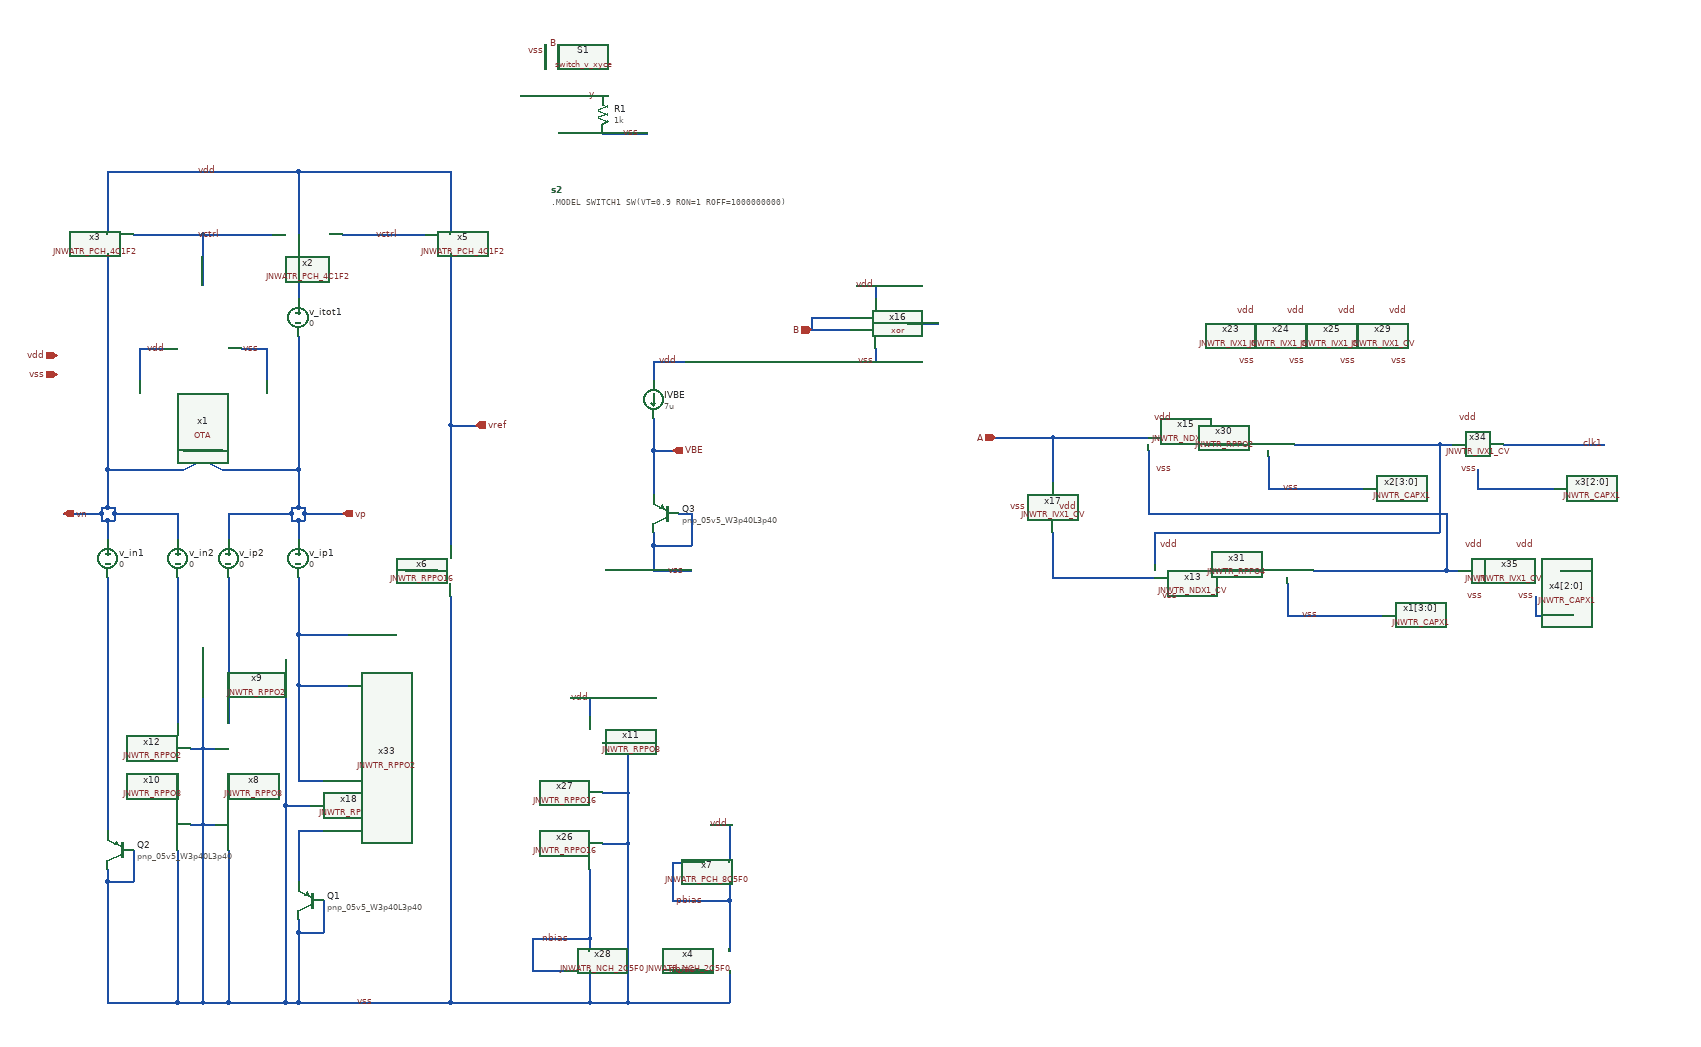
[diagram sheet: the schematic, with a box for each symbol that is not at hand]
v {xschem version=3.4.6 file_version=1.2}
G {}
K {}
V {}
S {}
E {}
N 870 -120 960 -120 {
lab=nbias}
N 960 -120 960 -100 {
lab=nbias}
N 1180 -210 1180 -180 {
lab=pbias}
N 1090 -180 1180 -180 {
lab=pbias}
N 1090 -240 1090 -180 {
lab=pbias}
N 1090 -240 1140 -240 {
lab=pbias}
N 1180 -300 1180 -240 {
lab=vdd}
N 960 -70 960 -20 {
lab=vss}
N 930 -500 960 -500 {
lab=vdd}
N 1020 -270 1020 -20 {
lab=vss}
N 980 -270 1020 -270 {
lab=vss}
N 1020 -350 1020 -270 {
lab=vss}
N 980 -350 1020 -350 {
lab=vss}
N 1020 -430 1020 -350 {
lab=vss}
N 980 -430 1020 -430 {
lab=vss}
N 960 -500 960 -470 {
lab=vdd}
N 1090 -70 1140 -70 {
lab=nbias}
N 1020 -20 1180 -20 {
lab=vss}
N 1150 -300 1180 -300 {
lab=vdd}
N 870 -120 870 -70 {
lab=nbias}
N 870 -70 920 -70 {
lab=nbias}
N 1180 -70 1180 -20 {
lab=vss}
N 1180 -180 1180 -100 {
lab=pbias}
N 960 -230 960 -120 {
lab=nbias}
N 490 -790 490 -780 {
lab=vp}
N 500 -800 510 -800 {
lab=vp}
N 210 -790 210 -780 {
lab=vn}
N 200 -800 210 -800 {
lab=vn}
N 510 -790 510 -780 {
lab=vp}
N 210 -800 210 -790 {
lab=vn}
N 490 -800 490 -790 {
lab=vp}
N 390 -790 490 -790 {
lab=vp}
N 200 -780 210 -780 {
lab=vn}
N 210 -790 310 -790 {
lab=vn}
N 190 -790 190 -780 {
lab=vn}
N 240 -260 240 -210 {
lab=vss}
N 200 -210 240 -210 {
lab=vss}
N 200 -230 200 -210 {
lab=vss}
N 540 -180 540 -130 {
lab=vss}
N 500 -130 540 -130 {
lab=vss}
N 500 -150 500 -130 {
lab=vss}
N 500 -780 510 -780 {
lab=vp}
N 380 -860 500 -860 {
lab=vp}
N 200 -860 200 -800 {
lab=vn}
N 190 -800 200 -800 {
lab=vn}
N 500 -860 500 -800 {
lab=vp}
N 490 -800 500 -800 {
lab=vp}
N 200 -1200 200 -860 {
lab=vn}
N 200 -860 320 -860 {
lab=vn}
N 350 -1230 350 -1150 {
lab=vctrl}
N 350 -1230 460 -1230 {
lab=vctrl}
N 240 -1230 350 -1230 {
lab=vctrl}
N 200 -1330 200 -1230 {
lab=vdd}
N 200 -1330 500 -1330 {
lab=vdd}
N 740 -1330 740 -1230 {
lab=vdd}
N 500 -1330 740 -1330 {
lab=vdd}
N 500 -1330 500 -1230 {
lab=vdd}
N 740 -930 740 -740 {
lab=vref}
N 510 -790 570 -790 {
lab=vp}
N 510 -800 510 -790 {
lab=vp}
N 130 -790 190 -790 {
lab=vn}
N 190 -800 190 -790 {
lab=vn}
N 740 -930 780 -930 {
lab=vref}
N 740 -1200 740 -930 {
lab=vref}
N 570 -1230 700 -1230 {
lab=vctrl}
N 500 -130 500 -20 {
lab=vss}
N 200 -210 200 -20 {
lab=vss}
N 500 -20 740 -20 {
lab=vss}
N 670 -700 720 -700 {
lab=vss}
N 740 -660 740 -20 {
lab=vss}
N 960 -20 1020 -20 {
lab=vss}
N 740 -20 960 -20 {
lab=vss}
N 480 -20 500 -20 {
lab=vss}
N 500 -1200 500 -1130 {
lab=#net1}
N 500 -780 500 -750 {
lab=vp}
N 490 -780 500 -780 {
lab=vp}
N 390 -790 390 -750 {
lab=vp}
N 200 -780 200 -750 {
lab=vn}
N 190 -780 200 -780 {
lab=vn}
N 200 -690 200 -290 {
lab=#net2}
N 310 -790 310 -750 {
lab=vn}
N 1060 -890 1060 -820 {
lab=VBE}
N 1060 -740 1060 -700 {
lab=vss}
N 1060 -700 1120 -700 {
lab=vss}
N 1060 -1030 1060 -1000 {
lab=vdd}
N 1060 -1030 1110 -1030 {
lab=vdd}
N 1060 -890 1090 -890 {
lab=VBE}
N 1060 -940 1060 -890 {
lab=VBE}
N 1100 -790 1120 -790 {
lab=vss}
N 1120 -790 1120 -740 {
lab=vss}
N 1060 -740 1120 -740 {
lab=vss}
N 1060 -760 1060 -740 {
lab=vss}
N 1310 -1100 1370 -1100 {
lab=B}
N 1310 -1080 1370 -1080 {
lab=B}
N 1410 -1150 1410 -1130 {
lab=vdd}
N 1380 -1150 1410 -1150 {
lab=vdd}
N 1410 -1050 1410 -1030 {
lab=vss}
N 1380 -1030 1410 -1030 {
lab=vss}
N 1460 -1090 1510 -1090 {
lab=#net3}
N 500 -520 500 -370 {
lab=#net4}
N 350 -300 370 -300 {
lab=vss}
N 330 -300 350 -300 {
lab=vss}
N 350 -420 370 -420 {
lab=vss}
N 330 -420 350 -420 {
lab=vss}
N 350 -420 350 -300 {
lab=vss}
N 350 -580 350 -420 {
lab=vss}
N 500 -520 580 -520 {
lab=#net4}
N 500 -600 580 -600 {
lab=#net4}
N 310 -690 310 -460 {
lab=#net5}
N 390 -690 390 -460 {
lab=#net6}
N 500 -690 500 -600 {
lab=#net4}
N 500 -290 500 -210 {
lab=#net7}
N 480 -330 480 -20 {
lab=vss}
N 390 -20 480 -20 {
lab=vss}
N 350 -300 350 -20 {
lab=vss}
N 310 -260 310 -20 {
lab=vss}
N 200 -20 310 -20 {
lab=vss}
N 390 -260 390 -20 {
lab=vss}
N 350 -20 390 -20 {
lab=vss}
N 310 -20 350 -20 {
lab=vss}
N 500 -1070 500 -860 {
lab=vp}
N 320 -860 380 -890 {
lab=vn}
N 320 -890 380 -860 {
lab=vp}
N 250 -1050 250 -1000 {
lab=vdd}
N 250 -1050 290 -1050 {
lab=vdd}
N 450 -1050 450 -1000 {
lab=vss}
N 410 -1050 450 -1050 {
lab=vss}
N 940 -1450 980 -1450 {
lab=y}
N 890 -1530 890 -1490 {
lab=vss}
N 910 -1530 910 -1490 {
lab=B}
N 850 -1450 880 -1450 {
lab=#net8}
N 980 -1390 1050 -1390 {
lab=vss}
N 1690 -760 1690 -690 {
lab=#net9}
N 1690 -690 1850 -690 {
lab=#net9}
N 1690 -910 1840 -910 {
lab=A}
N 1690 -910 1690 -840 {
lab=A}
N 1600 -910 1690 -910 {
lab=A}
N 1940 -700 2020 -700 {
lab=#net10}
N 2310 -790 2310 -700 {
lab=#net11}
N 1840 -790 2310 -790 {
lab=#net11}
N 1840 -890 1840 -790 {
lab=#net11}
N 1930 -900 1990 -900 {
lab=#net12}
N 2300 -900 2300 -760 {
lab=#net13}
N 1850 -760 2300 -760 {
lab=#net13}
N 1850 -760 1850 -710 {
lab=#net13}
N 1310 -1100 1310 -1080 {
lab=B}
N 2300 -900 2320 -900 {
lab=#net13}
N 2060 -680 2060 -630 {
lab=vss}
N 2100 -700 2310 -700 {
lab=#net11}
N 2060 -630 2210 -630 {
lab=vss}
N 2030 -880 2030 -830 {
lab=vss}
N 2070 -900 2300 -900 {
lab=#net13}
N 2030 -830 2180 -830 {
lab=vss}
N 2310 -700 2330 -700 {
lab=#net11}
N 2400 -900 2560 -900 {
lab=clk1}
N 2490 -700 2530 -700 {
lab=clk2}
N 2450 -660 2450 -630 {
lab=vss}
N 2450 -630 2510 -630 {
lab=vss}
N 2360 -860 2360 -830 {
lab=vss}
N 2360 -830 2480 -830 {
lab=vss}
N 480 -330 520 -330 {lab=vss}
N 480 -560 480 -330 {
lab=vss}
N 500 -370 540 -370 {lab=#net4}
N 500 -290 540 -290 {lab=#net7}
N 500 -600 500 -520 {lab=#net4}
N 390 -380 390 -340 {lab=#net14}
N 310 -380 310 -340 {lab=#net15}
C {devices/ipin.sym} 120 -1010 0 0 {name=p4 lab=vss}
C {devices/ipin.sym} 120 -1040 0 0 {name=p5 lab=vdd}
C {devices/lab_wire.sym} 1140 -180 0 0 {name=p32 sig_type=std_logic lab=pbias}
C {devices/lab_wire.sym} 960 -500 0 0 {name=p34 sig_type=std_logic lab=vdd}
C {JNW_ATR_SKY130A/JNWATR_PCH_8C5F0.sym} 1140 -240 0 0 {name=x7 }
C {JNW_ATR_SKY130A/JNWATR_NCH_2C5F0.sym} 920 -70 0 0 {name=x28 }
C {devices/lab_wire.sym} 930 -120 0 0 {name=p12 sig_type=std_logic lab=nbias}
C {devices/lab_wire.sym} 1180 -300 0 0 {name=p13 sig_type=std_logic lab=vdd}
C {JNW_ATR_SKY130A/JNWATR_NCH_2C5F0.sym} 1140 -70 0 0 {name=x4 }
C {devices/lab_wire.sym} 1130 -70 0 0 {name=p14 sig_type=std_logic lab=nbias}
C {JNW_TR_SKY130A/JNWTR_RPPO16.sym} 960 -230 3 0 {name=x26 }
C {JNW_TR_SKY130A/JNWTR_RPPO16.sym} 960 -310 3 0 {name=x27 }
C {JNW_TR_SKY130A/JNWTR_RPPO8.sym} 960 -390 3 0 {name=x11 }
C {sky130_fd_pr/pnp_05v5.sym} 520 -180 0 1 {name=Q1
model=pnp_05v5_W3p40L3p40
m=8
spiceprefix=X
}
C {sky130_fd_pr/pnp_05v5.sym} 220 -260 0 1 {name=Q2
model=pnp_05v5_W3p40L3p40
m=1
spiceprefix=X
}
C {devices/lab_wire.sym} 340 -1330 0 1 {name=p29 sig_type=std_logic lab=vdd

}
C {devices/opin.sym} 130 -790 2 0 {name=p44 lab=vn}
C {JNW_ATR_SKY130A/JNWATR_PCH_4C1F2.sym} 460 -1230 0 0 {name=x2 }
C {JNW_ATR_SKY130A/JNWATR_PCH_4C1F2.sym} 240 -1230 0 1 {name=x3 }
C {JNW_ATR_SKY130A/JNWATR_PCH_4C1F2.sym} 700 -1230 0 0 {name=x5 }
C {devices/lab_wire.sym} 340 -1230 0 1 {name=p8 sig_type=std_logic lab=vctrl

}
C {devices/lab_wire.sym} 620 -1230 0 1 {name=p9 sig_type=std_logic lab=vctrl

}
C {devices/lab_wire.sym} 620 -20 0 0 {name=p3 sig_type=std_logic lab=vss
}
C {devices/opin.sym} 570 -790 0 0 {name=p7 lab=vp}
C {devices/opin.sym} 780 -930 0 0 {name=p10 lab=vref}
C {devices/lab_wire.sym} 700 -700 0 0 {name=p11 sig_type=std_logic lab=vss
}
C {JNW_TR_SKY130A/JNWTR_RPPO16.sym} 740 -740 1 0 {name=x6 }
C {devices/vsource.sym} 500 -1100 0 0 {name=v_itot1 value=0 savecurrent=true}
C {devices/vsource.sym} 500 -720 0 0 {name=v_ip1 value=0 savecurrent=true}
C {devices/vsource.sym} 390 -720 0 0 {name=v_ip2 value=0 savecurrent=true}
C {devices/vsource.sym} 200 -720 0 0 {name=v_in1 value=0 savecurrent=true}
C {devices/vsource.sym} 310 -720 0 0 {name=v_in2 value=0 savecurrent=true}
C {devices/isource.sym} 1060 -970 0 0 {name=IVBE value=7u}
C {devices/lab_wire.sym} 1100 -1030 0 0 {name=p15 sig_type=std_logic lab=vdd}
C {devices/lab_wire.sym} 1110 -700 0 0 {name=p16 sig_type=std_logic lab=vss
}
C {devices/opin.sym} 1090 -890 0 0 {name=p17 lab=VBE}
C {sky130_fd_pr/pnp_05v5.sym} 1080 -790 0 1 {name=Q3
model=pnp_05v5_W3p40L3p40
m=1
spiceprefix=X
}
C {devices/ipin.sym} 1310 -1080 0 0 {name=p18 lab=B}
C {JNW_AVV_SKY130A/xor.sym} 1410 -1090 0 0 {name=x16}
C {devices/lab_wire.sym} 1410 -1150 0 0 {name=p20 sig_type=std_logic lab=vdd}
C {devices/lab_wire.sym} 1410 -1030 0 0 {name=p21 sig_type=std_logic lab=vss
}
C {JNW_TR_SKY130A/JNWTR_RPPO2.sym} 500 -370 1 0 {name=x18 }
C {JNW_AVV_SKY130A/OTA.sym} 350 -1000 3 0 {name=x1}
C {devices/lab_wire.sym} 260 -1050 0 1 {name=p1 sig_type=std_logic lab=vdd

}
C {devices/lab_wire.sym} 440 -1050 0 0 {name=p2 sig_type=std_logic lab=vss
}
C {devices/lab_wire.sym} 890 -1520 0 0 {name=p6 sig_type=std_logic lab=vss
}
C {devices/lab_wire.sym} 910 -1530 0 0 {name=p24 sig_type=std_logic lab=B
}
C {devices/lab_wire.sym} 970 -1450 0 0 {name=p25 sig_type=std_logic lab=y
}
C {devices/switch_v_xyce.sym} 910 -1450 1 0 {.MODEL SWITCH1 SW(VT=0.5 VH=0.01 RON=0.01 ROFF=10000000)

name=S1 model=SWITCH1 state=OFF

}
C {devices/netlist.sym} 900 -1300 0 0 {name=s2 value=".MODEL SWITCH1 SW(VT=0.9 RON=1 ROFF=1000000000)"
}
C {devices/res.sym} 980 -1420 0 0 {name=R1
value=1k
footprint=1206
device=resistor
m=1}
C {devices/lab_wire.sym} 1040 -1390 0 0 {name=p22 sig_type=std_logic lab=vss
}
C {JNW_TR_SKY130A/JNWTR_NDX1_CV.sym} 1850 -690 0 0 {name=x13 }
C {devices/lab_wire.sym} 1890 -740 0 0 {name=p26 sig_type=std_logic lab=vdd}
C {devices/lab_wire.sym} 1890 -660 0 0 {name=p27 sig_type=std_logic lab=vss
}
C {JNW_TR_SKY130A/JNWTR_NDX1_CV.sym} 1840 -890 0 0 {name=x15 }
C {devices/lab_wire.sym} 1880 -940 0 0 {name=p28 sig_type=std_logic lab=vdd}
C {devices/lab_wire.sym} 1880 -860 0 0 {name=p30 sig_type=std_logic lab=vss
}
C {JNW_TR_SKY130A/JNWTR_IVX1_CV.sym} 1690 -840 1 0 {name=x17 }
C {devices/lab_wire.sym} 1650 -800 0 0 {name=p31 sig_type=std_logic lab=vss
}
C {devices/lab_wire.sym} 1730 -800 0 0 {name=p33 sig_type=std_logic lab=vdd}
C {devices/ipin.sym} 1600 -910 0 0 {name=p35 lab=A}
C {JNW_TR_SKY130A/JNWTR_IVX1_CV.sym} 1970 -1070 0 0 {name=x23 }
C {devices/lab_wire.sym} 2010 -1030 3 0 {name=p36 sig_type=std_logic lab=vss
}
C {devices/lab_wire.sym} 2010 -1110 3 0 {name=p37 sig_type=std_logic lab=vdd}
C {JNW_TR_SKY130A/JNWTR_IVX1_CV.sym} 2050 -1070 0 0 {name=x24 }
C {devices/lab_wire.sym} 2090 -1030 3 0 {name=p38 sig_type=std_logic lab=vss
}
C {devices/lab_wire.sym} 2090 -1110 3 0 {name=p39 sig_type=std_logic lab=vdd}
C {JNW_TR_SKY130A/JNWTR_IVX1_CV.sym} 2130 -1070 0 0 {name=x25 }
C {devices/lab_wire.sym} 2170 -1030 3 0 {name=p40 sig_type=std_logic lab=vss
}
C {devices/lab_wire.sym} 2170 -1110 3 0 {name=p41 sig_type=std_logic lab=vdd}
C {JNW_TR_SKY130A/JNWTR_IVX1_CV.sym} 2210 -1070 0 0 {name=x29 }
C {devices/lab_wire.sym} 2250 -1030 3 0 {name=p42 sig_type=std_logic lab=vss
}
C {devices/lab_wire.sym} 2250 -1110 3 0 {name=p43 sig_type=std_logic lab=vdd}
C {devices/lab_wire.sym} 2560 -900 0 0 {name=p53 sig_type=std_logic lab=clk1}
C {devices/lab_wire.sym} 2530 -700 0 0 {name=p54 sig_type=std_logic lab=clk2}
C {JNW_TR_SKY130A/JNWTR_IVX1_CV.sym} 2320 -900 0 0 {name=x34 }
C {devices/lab_wire.sym} 2360 -860 3 0 {name=p19 sig_type=std_logic lab=vss
}
C {devices/lab_wire.sym} 2360 -940 3 0 {name=p23 sig_type=std_logic lab=vdd}
C {JNW_TR_SKY130A/JNWTR_CAPX1.sym} 2210 -640 0 0 {name=x1[3:0]}
C {devices/lab_wire.sym} 2110 -630 3 0 {name=p45 sig_type=std_logic lab=vss
}
C {JNW_TR_SKY130A/JNWTR_CAPX1.sym} 2180 -840 0 0 {name=x2[3:0]}
C {devices/lab_wire.sym} 2080 -830 3 0 {name=p46 sig_type=std_logic lab=vss
}
C {JNW_TR_SKY130A/JNWTR_IVX1_CV.sym} 2330 -700 0 0 {name=x32 }
C {devices/lab_wire.sym} 2370 -660 3 0 {name=p47 sig_type=std_logic lab=vss
}
C {devices/lab_wire.sym} 2370 -740 3 0 {name=p48 sig_type=std_logic lab=vdd}
C {JNW_TR_SKY130A/JNWTR_IVX1_CV.sym} 2410 -700 0 0 {name=x35 }
C {devices/lab_wire.sym} 2450 -660 3 0 {name=p51 sig_type=std_logic lab=vss
}
C {devices/lab_wire.sym} 2450 -740 3 0 {name=p52 sig_type=std_logic lab=vdd}
C {JNW_TR_SKY130A/JNWTR_CAPX1.sym} 2480 -840 0 0 {name=x3[2:0]}
C {JNW_TR_SKY130A/JNWTR_CAPX1.sym} 2510 -640 0 0 {name=x4[2:0]}
C {JNW_TR_SKY130A/JNWTR_RPPO4.sym} 2020 -700 0 0 {name=x31 }
C {JNW_TR_SKY130A/JNWTR_RPPO2.sym} 1990 -900 0 0 {name=x30 }
C {JNW_TR_SKY130A/JNWTR_RPPO2.sym} 540 -370 1 0 {name=x33 }
C {JNW_TR_SKY130A/JNWTR_RPPO8.sym} 390 -340 1 0 {name=x8 }
C {JNW_TR_SKY130A/JNWTR_RPPO2.sym} 390 -460 1 0 {name=x9 }
C {JNW_TR_SKY130A/JNWTR_RPPO8.sym} 310 -340 3 1 {name=x10 }
C {JNW_TR_SKY130A/JNWTR_RPPO2.sym} 310 -460 3 1 {name=x12 }
